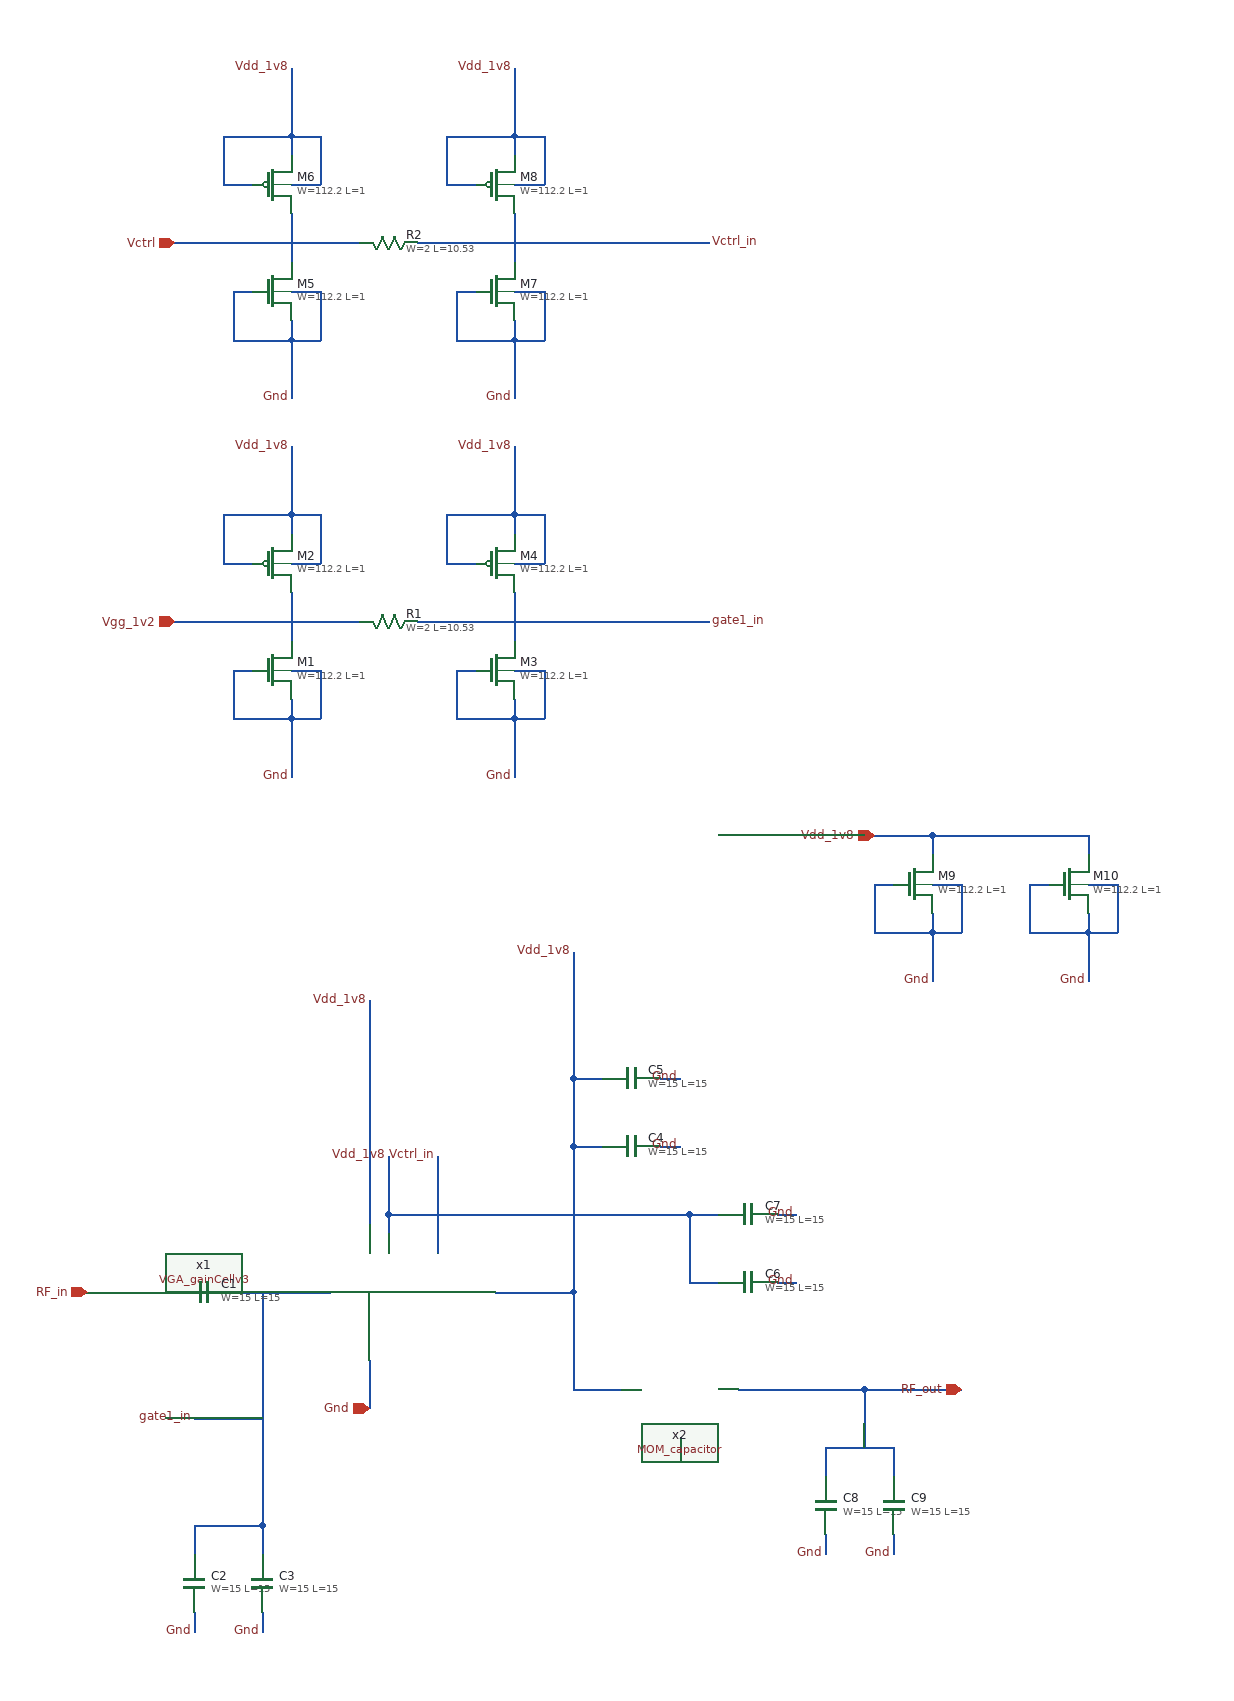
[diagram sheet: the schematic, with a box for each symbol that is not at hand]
v {xschem version=2.9.9 file_version=1.2 }
G {}
K {}
V {}
S {}
E {}
N 210 -210 310 -210 { lab=gate1_in}
N 50 -210 150 -210 { lab=RF_in}
N 350 -140 350 -90 { lab=Gnd}
N 240 -210 240 -110 { lab=gate1_in}
N 170 30 170 60 { lab=gate1_in}
N 170 30 240 30 { lab=gate1_in}
N 240 30 240 60 { lab=gate1_in}
N 170 120 170 140 { lab=Gnd}
N 240 120 240 140 { lab=Gnd}
N 480 -210 560 -210 { lab=Vdd_1v8}
N 560 -360 560 -210 { lab=Vdd_1v8}
N 560 -360 590 -360 { lab=Vdd_1v8}
N 560 -430 560 -360 { lab=Vdd_1v8}
N 560 -430 590 -430 { lab=Vdd_1v8}
N 650 -360 670 -360 { lab=Gnd}
N 650 -430 670 -430 { lab=Gnd}
N 680 -220 710 -220 { lab=Vdd_1v8}
N 680 -290 680 -220 { lab=Vdd_1v8}
N 680 -290 710 -290 { lab=Vdd_1v8}
N 770 -220 790 -220 { lab=Gnd}
N 770 -290 790 -290 { lab=Gnd}
N 370 -290 370 -270 { lab=Vdd_1v8}
N 370 -290 680 -290 { lab=Vdd_1v8}
N 420 -350 420 -250 { lab=Vctrl_in}
N 350 -510 350 -280 { lab=Vdd_1v8}
N 560 -210 560 -110 { lab=Vdd_1v8}
N 560 -110 610 -110 { lab=Vdd_1v8}
N 730 -110 860 -110 { lab=RF_out}
N 820 -50 820 -20 { lab=RF_out}
N 820 -50 890 -50 { lab=RF_out}
N 890 -50 890 -20 { lab=RF_out}
N 820 40 820 60 { lab=Gnd}
N 890 40 890 60 { lab=Gnd}
N 860 -110 860 -50 { lab=RF_out}
N 860 -110 960 -110 { lab=RF_out}
N 560 -460 560 -430 { lab=Vdd_1v8}
N 210 -850 230 -850 { lab=Gnd}
N 210 -850 210 -800 { lab=Gnd}
N 210 -800 270 -800 { lab=Gnd}
N 270 -820 270 -800 { lab=Gnd}
N 270 -850 300 -850 { lab=Gnd}
N 300 -850 300 -800 { lab=Gnd}
N 270 -800 300 -800 { lab=Gnd}
N 200 -960 230 -960 { lab=Vdd_1v8}
N 200 -1010 200 -960 { lab=Vdd_1v8}
N 200 -1010 270 -1010 { lab=Vdd_1v8}
N 270 -1010 270 -990 { lab=Vdd_1v8}
N 270 -960 300 -960 { lab=Vdd_1v8}
N 300 -1010 300 -960 { lab=Vdd_1v8}
N 270 -1010 300 -1010 { lab=Vdd_1v8}
N 270 -930 270 -880 { lab=Vgg_1v2}
N 270 -1080 270 -1010 { lab=Vdd_1v8}
N 270 -800 270 -740 { lab=Gnd}
N 270 -900 340 -900 { lab=Vgg_1v2}
N 400 -900 460 -900 { lab=gate1_in}
N 440 -850 460 -850 { lab=Gnd}
N 440 -850 440 -800 { lab=Gnd}
N 440 -800 500 -800 { lab=Gnd}
N 500 -820 500 -800 { lab=Gnd}
N 500 -850 530 -850 { lab=Gnd}
N 530 -850 530 -800 { lab=Gnd}
N 500 -800 530 -800 { lab=Gnd}
N 430 -960 460 -960 { lab=Vdd_1v8}
N 430 -1010 430 -960 { lab=Vdd_1v8}
N 430 -1010 500 -1010 { lab=Vdd_1v8}
N 500 -1010 500 -990 { lab=Vdd_1v8}
N 500 -960 530 -960 { lab=Vdd_1v8}
N 530 -1010 530 -960 { lab=Vdd_1v8}
N 500 -1010 530 -1010 { lab=Vdd_1v8}
N 500 -930 500 -880 { lab=gate1_in}
N 500 -1080 500 -1010 { lab=Vdd_1v8}
N 500 -800 500 -740 { lab=Gnd}
N 460 -900 500 -900 { lab=gate1_in}
N 150 -900 270 -900 { lab=Vgg_1v2}
N 500 -900 700 -900 { lab=gate1_in}
N 210 -1240 230 -1240 { lab=Gnd}
N 210 -1240 210 -1190 { lab=Gnd}
N 210 -1190 270 -1190 { lab=Gnd}
N 270 -1210 270 -1190 { lab=Gnd}
N 270 -1240 300 -1240 { lab=Gnd}
N 300 -1240 300 -1190 { lab=Gnd}
N 270 -1190 300 -1190 { lab=Gnd}
N 200 -1350 230 -1350 { lab=Vdd_1v8}
N 200 -1400 200 -1350 { lab=Vdd_1v8}
N 200 -1400 270 -1400 { lab=Vdd_1v8}
N 270 -1400 270 -1380 { lab=Vdd_1v8}
N 270 -1350 300 -1350 { lab=Vdd_1v8}
N 300 -1400 300 -1350 { lab=Vdd_1v8}
N 270 -1400 300 -1400 { lab=Vdd_1v8}
N 270 -1320 270 -1270 { lab=Vctrl}
N 270 -1470 270 -1400 { lab=Vdd_1v8}
N 270 -1190 270 -1130 { lab=Gnd}
N 270 -1290 340 -1290 { lab=Vctrl}
N 400 -1290 460 -1290 { lab=Vctrl_in}
N 440 -1240 460 -1240 { lab=Gnd}
N 440 -1240 440 -1190 { lab=Gnd}
N 440 -1190 500 -1190 { lab=Gnd}
N 500 -1210 500 -1190 { lab=Gnd}
N 500 -1240 530 -1240 { lab=Gnd}
N 530 -1240 530 -1190 { lab=Gnd}
N 500 -1190 530 -1190 { lab=Gnd}
N 430 -1350 460 -1350 { lab=Vdd_1v8}
N 430 -1400 430 -1350 { lab=Vdd_1v8}
N 430 -1400 500 -1400 { lab=Vdd_1v8}
N 500 -1400 500 -1380 { lab=Vdd_1v8}
N 500 -1350 530 -1350 { lab=Vdd_1v8}
N 530 -1400 530 -1350 { lab=Vdd_1v8}
N 500 -1400 530 -1400 { lab=Vdd_1v8}
N 500 -1320 500 -1270 { lab=Vctrl_in}
N 500 -1470 500 -1400 { lab=Vdd_1v8}
N 500 -1190 500 -1130 { lab=Gnd}
N 460 -1290 500 -1290 { lab=Vctrl_in}
N 150 -1290 270 -1290 { lab=Vctrl}
N 500 -1290 700 -1290 { lab=Vctrl_in}
N 370 -350 370 -290 { lab=Vdd_1v8}
N 240 -110 240 30 { lab=gate1_in}
N 170 -80 240 -80 { lab=gate1_in}
N 560 -560 560 -460 { lab=Vdd_1v8}
N 870 -630 890 -630 { lab=Gnd}
N 870 -630 870 -580 { lab=Gnd}
N 870 -580 930 -580 { lab=Gnd}
N 930 -600 930 -580 { lab=Gnd}
N 930 -630 960 -630 { lab=Gnd}
N 960 -630 960 -580 { lab=Gnd}
N 930 -580 960 -580 { lab=Gnd}
N 860 -680 930 -680 { lab=Vdd_1v8}
N 930 -680 930 -660 { lab=Vdd_1v8}
N 930 -580 930 -530 { lab=Gnd}
N 1030 -630 1050 -630 { lab=Gnd}
N 1030 -630 1030 -580 { lab=Gnd}
N 1030 -580 1090 -580 { lab=Gnd}
N 1090 -600 1090 -580 { lab=Gnd}
N 1090 -630 1120 -630 { lab=Gnd}
N 1120 -630 1120 -580 { lab=Gnd}
N 1090 -580 1120 -580 { lab=Gnd}
N 1090 -680 1090 -660 { lab=Vdd_1v8}
N 1090 -580 1090 -530 { lab=Gnd}
N 930 -680 1090 -680 { lab=Vdd_1v8}
N 670 -60 670 -40 { lab=Gnd}
C {/home/leonardo/sky130_projects/SSCS_PICO_tapeout/VGA_tapeout/xschem/VGA_core/VGA_gainCellv3.sym} 390 -210 0 0 {name=x1}
C {sky130_fd_pr/cap_mim_m3_2.sym} 180 -210 1 0 {name=C1 model=cap_mim_m3_2 W=15 L=15 MF=1 spiceprefix=X}
C {devices/iopin.sym} 60 -210 2 0 {name=p1 lab=RF_in}
C {devices/iopin.sym} 350 -90 1 0 {name=p2 lab=Gnd}
C {sky130_fd_pr/cap_mim_m3_2.sym} 170 90 2 0 {name=C2 model=cap_mim_m3_2 W=15 L=15 MF=1 spiceprefix=X}
C {sky130_fd_pr/cap_mim_m3_2.sym} 240 90 2 0 {name=C3 model=cap_mim_m3_2 W=15 L=15 MF=1 spiceprefix=X}
C {devices/lab_pin.sym} 170 140 0 0 {name=l1 sig_type=std_logic lab=Gnd}
C {devices/lab_pin.sym} 240 140 0 0 {name=l2 sig_type=std_logic lab=Gnd}
C {sky130_fd_pr/cap_mim_m3_2.sym} 620 -360 1 0 {name=C4 model=cap_mim_m3_2 W=15 L=15 MF=1 spiceprefix=X}
C {sky130_fd_pr/cap_mim_m3_2.sym} 620 -430 1 0 {name=C5 model=cap_mim_m3_2 W=15 L=15 MF=1 spiceprefix=X}
C {devices/lab_pin.sym} 670 -360 3 0 {name=l3 sig_type=std_logic lab=Gnd}
C {devices/lab_pin.sym} 670 -430 3 0 {name=l4 sig_type=std_logic lab=Gnd}
C {sky130_fd_pr/cap_mim_m3_2.sym} 740 -220 1 0 {name=C6 model=cap_mim_m3_2 W=15 L=15 MF=1 spiceprefix=X}
C {sky130_fd_pr/cap_mim_m3_2.sym} 740 -290 1 0 {name=C7 model=cap_mim_m3_2 W=15 L=15 MF=1 spiceprefix=X}
C {devices/lab_pin.sym} 790 -220 3 0 {name=l6 sig_type=std_logic lab=Gnd}
C {devices/lab_pin.sym} 790 -290 3 0 {name=l7 sig_type=std_logic lab=Gnd}
C {sky130_fd_pr/cap_mim_m3_2.sym} 820 10 2 0 {name=C8 model=cap_mim_m3_2 W=15 L=15 MF=1 spiceprefix=X}
C {sky130_fd_pr/cap_mim_m3_2.sym} 890 10 2 0 {name=C9 model=cap_mim_m3_2 W=15 L=15 MF=1 spiceprefix=X}
C {devices/lab_pin.sym} 820 60 0 0 {name=l9 sig_type=std_logic lab=Gnd}
C {devices/lab_pin.sym} 890 60 0 0 {name=l10 sig_type=std_logic lab=Gnd}
C {devices/iopin.sym} 960 -110 0 0 {name=p3 lab=RF_out}
C {devices/iopin.sym} 870 -680 2 0 {name=p4 lab=Vdd_1v8}
C {devices/iopin.sym} 150 -900 2 0 {name=p5 lab=Vgg_1v2}
C {sky130_fd_pr/nfet_01v8_lvt.sym} 250 -850 0 0 {name=M1
L=1
W=112.2
nf=20
mult=1
ad="'int((nf+1)/2) * W/nf * 0.29'" 
pd="'2*int((nf+1)/2) * (W/nf + 0.29)'"
as="'int((nf+2)/2) * W/nf * 0.29'" 
ps="'2*int((nf+2)/2) * (W/nf + 0.29)'"
nrd="'0.29 / W'" nrs="'0.29 / W'"
sa=0 sb=0 sd=0
model=nfet_01v8_lvt
spiceprefix=X
}
C {sky130_fd_pr/pfet_01v8_lvt.sym} 250 -960 0 0 {name=M2
L=1
W=112.2
nf=20
mult=1
ad="'int((nf+1)/2) * W/nf * 0.29'" 
pd="'2*int((nf+1)/2) * (W/nf + 0.29)'"
as="'int((nf+2)/2) * W/nf * 0.29'" 
ps="'2*int((nf+2)/2) * (W/nf + 0.29)'"
nrd="'0.29 / W'" nrs="'0.29 / W'"
sa=0 sb=0 sd=0
model=pfet_01v8_lvt
spiceprefix=X
}
C {devices/lab_pin.sym} 270 -1080 0 0 {name=l12 sig_type=std_logic lab=Vdd_1v8}
C {devices/lab_pin.sym} 270 -740 0 0 {name=l13 sig_type=std_logic lab=Gnd}
C {sky130_fd_pr/res_generic_po.sym} 370 -900 1 0 {name=R1
W=2
L=10.53
model=res_generic_po
mult=1}
C {sky130_fd_pr/nfet_01v8_lvt.sym} 480 -850 0 0 {name=M3
L=1
W=112.2
nf=20
mult=1
ad="'int((nf+1)/2) * W/nf * 0.29'" 
pd="'2*int((nf+1)/2) * (W/nf + 0.29)'"
as="'int((nf+2)/2) * W/nf * 0.29'" 
ps="'2*int((nf+2)/2) * (W/nf + 0.29)'"
nrd="'0.29 / W'" nrs="'0.29 / W'"
sa=0 sb=0 sd=0
model=nfet_01v8_lvt
spiceprefix=X
}
C {sky130_fd_pr/pfet_01v8_lvt.sym} 480 -960 0 0 {name=M4
L=1
W=112.2
nf=20
mult=1
ad="'int((nf+1)/2) * W/nf * 0.29'" 
pd="'2*int((nf+1)/2) * (W/nf + 0.29)'"
as="'int((nf+2)/2) * W/nf * 0.29'" 
ps="'2*int((nf+2)/2) * (W/nf + 0.29)'"
nrd="'0.29 / W'" nrs="'0.29 / W'"
sa=0 sb=0 sd=0
model=pfet_01v8_lvt
spiceprefix=X
}
C {devices/lab_pin.sym} 500 -1080 0 0 {name=l14 sig_type=std_logic lab=Vdd_1v8}
C {devices/lab_pin.sym} 500 -740 0 0 {name=l15 sig_type=std_logic lab=Gnd}
C {devices/lab_pin.sym} 700 -900 2 0 {name=l16 sig_type=std_logic lab=gate1_in}
C {sky130_fd_pr/nfet_01v8_lvt.sym} 250 -1240 0 0 {name=M5
L=1
W=112.2
nf=20
mult=1
ad="'int((nf+1)/2) * W/nf * 0.29'" 
pd="'2*int((nf+1)/2) * (W/nf + 0.29)'"
as="'int((nf+2)/2) * W/nf * 0.29'" 
ps="'2*int((nf+2)/2) * (W/nf + 0.29)'"
nrd="'0.29 / W'" nrs="'0.29 / W'"
sa=0 sb=0 sd=0
model=nfet_01v8_lvt
spiceprefix=X
}
C {sky130_fd_pr/pfet_01v8_lvt.sym} 250 -1350 0 0 {name=M6
L=1
W=112.2
nf=20
mult=1
ad="'int((nf+1)/2) * W/nf * 0.29'" 
pd="'2*int((nf+1)/2) * (W/nf + 0.29)'"
as="'int((nf+2)/2) * W/nf * 0.29'" 
ps="'2*int((nf+2)/2) * (W/nf + 0.29)'"
nrd="'0.29 / W'" nrs="'0.29 / W'"
sa=0 sb=0 sd=0
model=pfet_01v8_lvt
spiceprefix=X
}
C {devices/lab_pin.sym} 270 -1470 0 0 {name=l19 sig_type=std_logic lab=Vdd_1v8}
C {devices/lab_pin.sym} 270 -1130 0 0 {name=l20 sig_type=std_logic lab=Gnd}
C {sky130_fd_pr/res_generic_po.sym} 370 -1290 1 0 {name=R2
W=2
L=10.53
model=res_generic_po
mult=1}
C {sky130_fd_pr/nfet_01v8_lvt.sym} 480 -1240 0 0 {name=M7
L=1
W=112.2
nf=20
mult=1
ad="'int((nf+1)/2) * W/nf * 0.29'" 
pd="'2*int((nf+1)/2) * (W/nf + 0.29)'"
as="'int((nf+2)/2) * W/nf * 0.29'" 
ps="'2*int((nf+2)/2) * (W/nf + 0.29)'"
nrd="'0.29 / W'" nrs="'0.29 / W'"
sa=0 sb=0 sd=0
model=nfet_01v8_lvt
spiceprefix=X
}
C {sky130_fd_pr/pfet_01v8_lvt.sym} 480 -1350 0 0 {name=M8
L=1
W=112.2
nf=20
mult=1
ad="'int((nf+1)/2) * W/nf * 0.29'" 
pd="'2*int((nf+1)/2) * (W/nf + 0.29)'"
as="'int((nf+2)/2) * W/nf * 0.29'" 
ps="'2*int((nf+2)/2) * (W/nf + 0.29)'"
nrd="'0.29 / W'" nrs="'0.29 / W'"
sa=0 sb=0 sd=0
model=pfet_01v8_lvt
spiceprefix=X
}
C {devices/lab_pin.sym} 500 -1470 0 0 {name=l21 sig_type=std_logic lab=Vdd_1v8}
C {devices/lab_pin.sym} 500 -1130 0 0 {name=l22 sig_type=std_logic lab=Gnd}
C {devices/lab_pin.sym} 700 -1290 2 0 {name=l23 sig_type=std_logic lab=Vctrl_in}
C {devices/iopin.sym} 150 -1290 2 0 {name=p6 lab=Vctrl}
C {devices/lab_pin.sym} 170 -80 0 0 {name=l18 sig_type=std_logic lab=gate1_in}
C {devices/lab_pin.sym} 350 -510 0 0 {name=l24 sig_type=std_logic lab=Vdd_1v8}
C {devices/lab_pin.sym} 420 -350 1 0 {name=l25 sig_type=std_logic lab=Vctrl_in}
C {devices/lab_pin.sym} 560 -560 0 0 {name=l26 sig_type=std_logic lab=Vdd_1v8}
C {sky130_fd_pr/nfet_01v8_lvt.sym} 910 -630 0 0 {name=M9
L=1
W=112.2
nf=20
mult=1
ad="'int((nf+1)/2) * W/nf * 0.29'" 
pd="'2*int((nf+1)/2) * (W/nf + 0.29)'"
as="'int((nf+2)/2) * W/nf * 0.29'" 
ps="'2*int((nf+2)/2) * (W/nf + 0.29)'"
nrd="'0.29 / W'" nrs="'0.29 / W'"
sa=0 sb=0 sd=0
model=nfet_01v8_lvt
spiceprefix=X
}
C {devices/lab_pin.sym} 930 -530 0 0 {name=l11 sig_type=std_logic lab=Gnd}
C {sky130_fd_pr/nfet_01v8_lvt.sym} 1070 -630 0 0 {name=M10
L=1
W=112.2
nf=20
mult=1
ad="'int((nf+1)/2) * W/nf * 0.29'" 
pd="'2*int((nf+1)/2) * (W/nf + 0.29)'"
as="'int((nf+2)/2) * W/nf * 0.29'" 
ps="'2*int((nf+2)/2) * (W/nf + 0.29)'"
nrd="'0.29 / W'" nrs="'0.29 / W'"
sa=0 sb=0 sd=0
model=nfet_01v8_lvt
spiceprefix=X
}
C {devices/lab_pin.sym} 1090 -530 0 0 {name=l27 sig_type=std_logic lab=Gnd}
C {devices/lab_pin.sym} 370 -350 1 0 {name=l17 sig_type=std_logic lab=Vdd_1v8}
C {devices/lab_pin.sym} 670 -40 0 0 {name=l5 sig_type=std_logic lab=Gnd}
C {/home/leonardo/sky130_projects/SSCS_PICO_tapeout/VGA_tapeout/xschem/MOM_capacitor/MOM_capacitor.sym} 670 -110 0 0 {name=x2}
